VERSION 5.7 ;
  NOWIREEXTENSIONATPIN ON ;
  DIVIDERCHAR "/" ;
  BUSBITCHARS "[]" ;
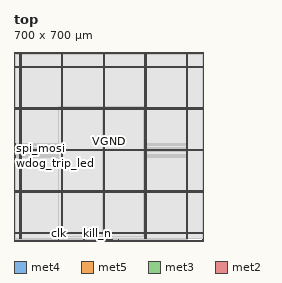
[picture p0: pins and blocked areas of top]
MACRO top
  CLASS BLOCK ;
  FOREIGN top ;
  ORIGIN 0.000 0.000 ;
  SIZE 700.000 BY 700.000 ;
  PIN VGND
    DIRECTION INOUT ;
    USE GROUND ;
    PORT
      LAYER met4 ;
        RECT 24.340 10.640 25.940 688.400 ;
    END
    PORT
      LAYER met4 ;
        RECT 177.940 10.640 179.540 688.400 ;
    END
    PORT
      LAYER met4 ;
        RECT 331.540 10.640 333.140 688.400 ;
    END
    PORT
      LAYER met4 ;
        RECT 485.140 10.640 486.740 688.400 ;
    END
    PORT
      LAYER met4 ;
        RECT 638.740 10.640 640.340 688.400 ;
    END
    PORT
      LAYER met5 ;
        RECT 5.280 30.030 694.380 31.630 ;
    END
    PORT
      LAYER met5 ;
        RECT 5.280 183.210 694.380 184.810 ;
    END
    PORT
      LAYER met5 ;
        RECT 5.280 336.390 694.380 337.990 ;
    END
    PORT
      LAYER met5 ;
        RECT 5.280 489.570 694.380 491.170 ;
    END
    PORT
      LAYER met5 ;
        RECT 5.280 642.750 694.380 644.350 ;
    END
  END VGND
  PIN VPWR
    DIRECTION INOUT ;
    USE POWER ;
    PORT
      LAYER met4 ;
        RECT 21.040 10.640 22.640 688.400 ;
    END
    PORT
      LAYER met4 ;
        RECT 174.640 10.640 176.240 688.400 ;
    END
    PORT
      LAYER met4 ;
        RECT 328.240 10.640 329.840 688.400 ;
    END
    PORT
      LAYER met4 ;
        RECT 481.840 10.640 483.440 688.400 ;
    END
    PORT
      LAYER met4 ;
        RECT 635.440 10.640 637.040 688.400 ;
    END
    PORT
      LAYER met5 ;
        RECT 5.280 26.730 694.380 28.330 ;
    END
    PORT
      LAYER met5 ;
        RECT 5.280 179.910 694.380 181.510 ;
    END
    PORT
      LAYER met5 ;
        RECT 5.280 333.090 694.380 334.690 ;
    END
    PORT
      LAYER met5 ;
        RECT 5.280 486.270 694.380 487.870 ;
    END
    PORT
      LAYER met5 ;
        RECT 5.280 639.450 694.380 641.050 ;
    END
  END VPWR
  PIN armed_led
    DIRECTION OUTPUT ;
    USE SIGNAL ;
    ANTENNADIFFAREA 0.891000 ;
    PORT
      LAYER met3 ;
        RECT 0.000 309.440 4.000 310.040 ;
    END
  END armed_led
  PIN clk
    DIRECTION INPUT ;
    USE SIGNAL ;
    ANTENNAGATEAREA 0.852000 ;
    ANTENNADIFFAREA 0.434700 ;
    PORT
      LAYER met2 ;
        RECT 164.310 0.000 164.590 4.000 ;
    END
  END clk
  PIN flow_pulse
    DIRECTION INPUT ;
    USE SIGNAL ;
    ANTENNAGATEAREA 0.213000 ;
    PORT
      LAYER met3 ;
        RECT 0.000 353.640 4.000 354.240 ;
    END
  END flow_pulse
  PIN kill_n
    DIRECTION OUTPUT ;
    USE SIGNAL ;
    ANTENNADIFFAREA 0.891000 ;
    PORT
      LAYER met2 ;
        RECT 305.990 0.000 306.270 4.000 ;
    END
  END kill_n
  PIN pwm_out[0]
    DIRECTION OUTPUT ;
    USE SIGNAL ;
    ANTENNADIFFAREA 0.891000 ;
    PORT
      LAYER met2 ;
        RECT 341.410 0.000 341.690 4.000 ;
    END
  END pwm_out[0]
  PIN pwm_out[1]
    DIRECTION OUTPUT ;
    USE SIGNAL ;
    ANTENNADIFFAREA 0.891000 ;
    PORT
      LAYER met2 ;
        RECT 363.950 0.000 364.230 4.000 ;
    END
  END pwm_out[1]
  PIN pwm_out[2]
    DIRECTION OUTPUT ;
    USE SIGNAL ;
    ANTENNADIFFAREA 0.891000 ;
    PORT
      LAYER met2 ;
        RECT 357.510 0.000 357.790 4.000 ;
    END
  END pwm_out[2]
  PIN pwm_out[3]
    DIRECTION OUTPUT ;
    USE SIGNAL ;
    ANTENNADIFFAREA 0.891000 ;
    PORT
      LAYER met2 ;
        RECT 360.730 0.000 361.010 4.000 ;
    END
  END pwm_out[3]
  PIN pwm_out[4]
    DIRECTION OUTPUT ;
    USE SIGNAL ;
    ANTENNADIFFAREA 0.891000 ;
    PORT
      LAYER met2 ;
        RECT 351.070 0.000 351.350 4.000 ;
    END
  END pwm_out[4]
  PIN pwm_out[5]
    DIRECTION OUTPUT ;
    USE SIGNAL ;
    ANTENNADIFFAREA 0.891000 ;
    PORT
      LAYER met2 ;
        RECT 344.630 0.000 344.910 4.000 ;
    END
  END pwm_out[5]
  PIN pwm_out[6]
    DIRECTION OUTPUT ;
    USE SIGNAL ;
    ANTENNADIFFAREA 0.891000 ;
    PORT
      LAYER met2 ;
        RECT 354.290 0.000 354.570 4.000 ;
    END
  END pwm_out[6]
  PIN pwm_out[7]
    DIRECTION OUTPUT ;
    USE SIGNAL ;
    ANTENNADIFFAREA 0.891000 ;
    PORT
      LAYER met2 ;
        RECT 347.850 0.000 348.130 4.000 ;
    END
  END pwm_out[7]
  PIN spi_cs_n
    DIRECTION INPUT ;
    USE SIGNAL ;
    ANTENNAGATEAREA 0.126000 ;
    PORT
      LAYER met3 ;
        RECT 0.000 343.440 4.000 344.040 ;
    END
  END spi_cs_n
  PIN spi_miso
    DIRECTION OUTPUT ;
    USE SIGNAL ;
    ANTENNADIFFAREA 0.891000 ;
    PORT
      LAYER met3 ;
        RECT 0.000 329.840 4.000 330.440 ;
    END
  END spi_miso
  PIN spi_mosi
    DIRECTION INPUT ;
    USE SIGNAL ;
    ANTENNAGATEAREA 0.159000 ;
    PORT
      LAYER met3 ;
        RECT 0.000 340.040 4.000 340.640 ;
    END
  END spi_mosi
  PIN spi_sclk
    DIRECTION INPUT ;
    USE SIGNAL ;
    ANTENNAGATEAREA 0.126000 ;
    PORT
      LAYER met3 ;
        RECT 0.000 357.040 4.000 357.640 ;
    END
  END spi_sclk
  PIN spray_pwm
    DIRECTION OUTPUT ;
    USE SIGNAL ;
    ANTENNADIFFAREA 0.891000 ;
    PORT
      LAYER met2 ;
        RECT 383.270 0.000 383.550 4.000 ;
    END
  END spray_pwm
  PIN wb_rst_i
    DIRECTION INPUT ;
    USE SIGNAL ;
    ANTENNAGATEAREA 0.213000 ;
    ANTENNADIFFAREA 0.434700 ;
    PORT
      LAYER met2 ;
        RECT 257.690 0.000 257.970 4.000 ;
    END
  END wb_rst_i
  PIN wdog_trip_led
    DIRECTION OUTPUT ;
    USE SIGNAL ;
    ANTENNADIFFAREA 0.891000 ;
    PORT
      LAYER met3 ;
        RECT 0.000 316.240 4.000 316.840 ;
    END
  END wdog_trip_led
  OBS
      LAYER nwell ;
        RECT 5.330 10.795 694.330 688.350 ;
      LAYER li1 ;
        RECT 5.520 10.795 694.140 688.245 ;
      LAYER met1 ;
        RECT 4.210 10.640 694.140 688.400 ;
      LAYER met2 ;
        RECT 4.230 4.280 640.310 688.345 ;
        RECT 4.230 4.000 164.030 4.280 ;
        RECT 164.870 4.000 257.410 4.280 ;
        RECT 258.250 4.000 305.710 4.280 ;
        RECT 306.550 4.000 341.130 4.280 ;
        RECT 341.970 4.000 344.350 4.280 ;
        RECT 345.190 4.000 347.570 4.280 ;
        RECT 348.410 4.000 350.790 4.280 ;
        RECT 351.630 4.000 354.010 4.280 ;
        RECT 354.850 4.000 357.230 4.280 ;
        RECT 358.070 4.000 360.450 4.280 ;
        RECT 361.290 4.000 363.670 4.280 ;
        RECT 364.510 4.000 382.990 4.280 ;
        RECT 383.830 4.000 640.310 4.280 ;
      LAYER met3 ;
        RECT 3.990 358.040 640.330 688.325 ;
        RECT 4.400 356.640 640.330 358.040 ;
        RECT 3.990 354.640 640.330 356.640 ;
        RECT 4.400 353.240 640.330 354.640 ;
        RECT 3.990 344.440 640.330 353.240 ;
        RECT 4.400 343.040 640.330 344.440 ;
        RECT 3.990 341.040 640.330 343.040 ;
        RECT 4.400 339.640 640.330 341.040 ;
        RECT 3.990 330.840 640.330 339.640 ;
        RECT 4.400 329.440 640.330 330.840 ;
        RECT 3.990 317.240 640.330 329.440 ;
        RECT 4.400 315.840 640.330 317.240 ;
        RECT 3.990 310.440 640.330 315.840 ;
        RECT 4.400 309.040 640.330 310.440 ;
        RECT 3.990 10.715 640.330 309.040 ;
      LAYER met4 ;
        RECT 164.975 17.175 174.240 494.185 ;
        RECT 176.640 17.175 177.540 494.185 ;
        RECT 179.940 17.175 327.840 494.185 ;
        RECT 330.240 17.175 331.140 494.185 ;
        RECT 333.540 17.175 475.345 494.185 ;
  END
END top
END LIBRARY

